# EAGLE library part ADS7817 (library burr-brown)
12-Bit Diff. Input Micro Power Sampling ADC

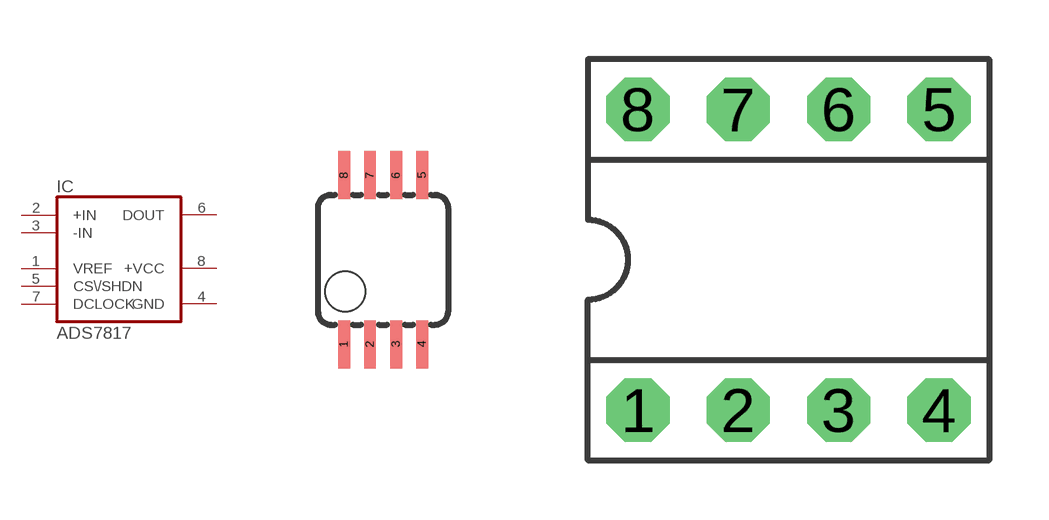
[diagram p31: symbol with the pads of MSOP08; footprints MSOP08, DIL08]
Designator prefix IC

## ADS7817E  [MSOP08]
1  VREF  in
2  +IN  in
3  -IN  in
4  GND  pwr
5  CS\/SHDN  in
6  DOUT  out
7  DCLOCK  in
8  +VCC  pwr

## ADS7817P  [DIL08]
Pads as for MSOP08

## ADS7817U  [SO08-GW]
Pads as for MSOP08

## Footprint MSOP08 (pad centres in mm)
Mini Small Outline Package
smd 0.3 x 1.2: 1 -0.976,-2.113; 2 -0.326,-2.113; 3 0.324,-2.113; 4 0.974,-2.113; 5 0.974,2.112; 6 0.324,2.112; 7 -0.326,2.112; 8 -0.976,2.112

## Footprint DIL08 (pad centres in mm)
Dual In Line
drill 0.813 pad 1.6 octagon: 1 -3.81,-3.81; 2 -1.27,-3.81; 3 1.27,-3.81; 4 3.81,-3.81; 5 3.81,3.81; 6 1.27,3.81; 7 -1.27,3.81; 8 -3.81,3.81

## Footprint SO08-GW (pad centres in mm)
Small Outline Package, gull wing
smd 0.762 x 2.21: 1 -3.81,-4.318; 2 -1.27,-4.318; 3 1.27,-4.318; 4 3.81,-4.318; 5 3.81,4.318; 6 1.27,4.318; 7 -1.27,4.318; 8 -3.81,4.318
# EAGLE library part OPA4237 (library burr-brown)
Single-Supply Operational Amplifiers MicroAmplifier(TM) Series

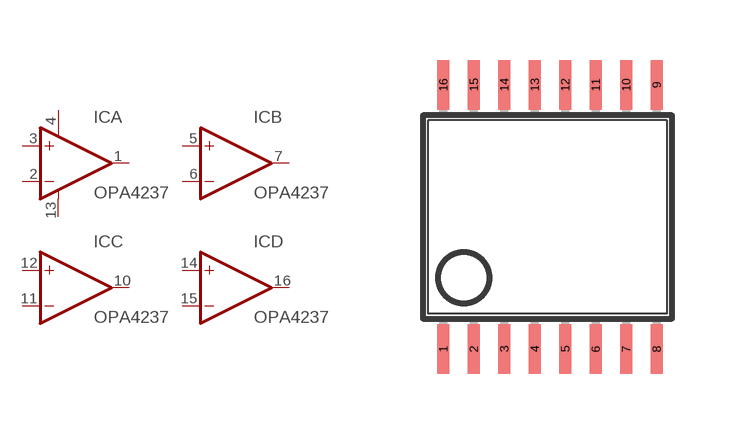
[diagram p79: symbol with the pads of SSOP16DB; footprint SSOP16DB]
Designator prefix IC; gates A=OP-AMP+- B=OP-AMP C=OP-AMP D=OP-AMP

## OPA4237U  [SSOP16DB]
1  A:OUT  out
2  A:-IN  in
3  A:+IN  in
4  A:V+  pwr
5  B:+IN  in
6  B:-IN  in
7  B:OUT  out
10  C:OUT  out
11  C:-IN  in
12  C:+IN  in
13  A:V-  pwr
14  D:+IN  in
15  D:-IN  in
16  D:OUT  out

## Footprint SSOP16DB (pad centres in mm)
Small Shrink Outline Package
smd 0.305 x 1.245: 1 -2.667,-3.302; 2 -1.905,-3.302; 3 -1.143,-3.302; 4 -0.381,-3.302; 5 0.381,-3.302; 6 1.143,-3.302; 7 1.905,-3.302; 8 2.667,-3.302; 9 2.667,3.302; 10 1.905,3.302; 11 1.143,3.302; 12 0.381,3.302; 13 -0.381,3.302; 14 -1.143,3.302; 15 -1.905,3.302; 16 -2.667,3.302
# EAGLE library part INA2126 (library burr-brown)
Instrumentation Amplifier Micropower, Single and Dual Versions

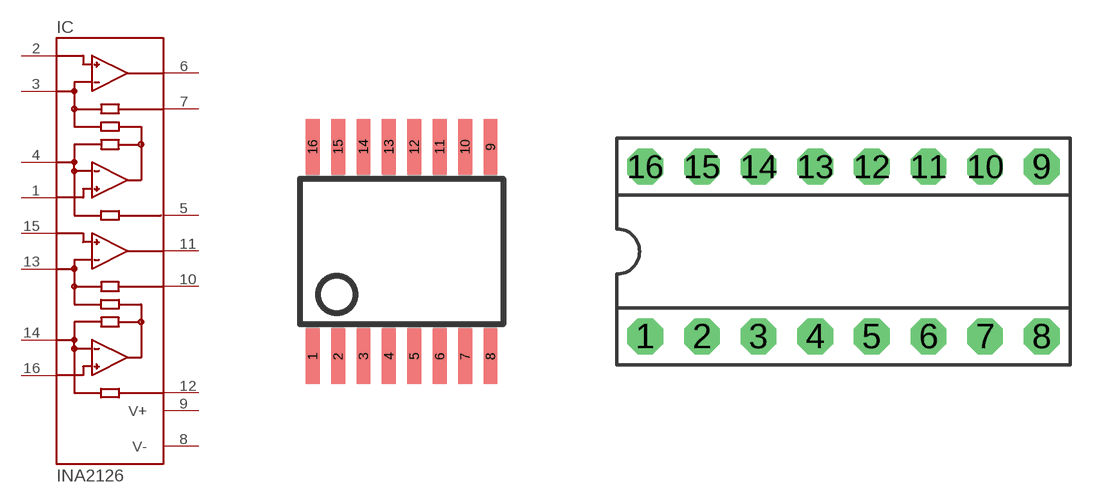
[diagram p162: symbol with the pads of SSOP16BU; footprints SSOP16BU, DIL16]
Designator prefix IC

## INA2126E  [SSOP16BU]
1  -INA  in
2  +INA  in
3  RGA  pas
4  RGA  pas
5  REFA  pwr
6  OUTA  out
7  SENSEA  pas
8  V-  pwr
9  V+  pwr
10  SENSEB  pas
11  OUTB  out
12  REFB  pwr
13  RGB  pas
14  RGB  pas
15  +INB  in
16  -INB  in

## INA2126P  [DIL16]
Pads as for SSOP16BU

## INA2126U  [SO16-1]
Pads as for SSOP16BU

## Footprint SSOP16BU (pad centres in mm)
Small Shrink Outline Package
smd 0.348 x 1.397: 1 -2.223,-2.619; 2 -1.588,-2.62; 3 -0.953,-2.62; 4 -0.318,-2.62; 5 0.318,-2.62; 6 0.953,-2.62; 7 1.588,-2.62; 8 2.223,-2.62; 9 2.223,2.62; 10 1.588,2.62; 11 0.953,2.62; 12 0.318,2.62; 13 -0.318,2.62; 14 -0.953,2.62; 15 -1.588,2.62; 16 -2.223,2.62

## Footprint DIL16 (pad centres in mm)
Dual In Line
drill 0.813 pad 1.6 octagon: 1 -8.89,-3.81; 2 -6.35,-3.81; 3 -3.81,-3.81; 4 -1.27,-3.81; 5 1.27,-3.81; 6 3.81,-3.81; 7 6.35,-3.81; 8 8.89,-3.81; 9 8.89,3.81; 10 6.35,3.81; 11 3.81,3.81; 12 1.27,3.81; 13 -1.27,3.81; 14 -3.81,3.81; 15 -6.35,3.81; 16 -8.89,3.81

## Footprint SO16-1 (pad centres in mm)
Small Outline Package
smd 0.762 x 1.524: 1 -4.445,-4.775; 2 -3.175,-4.775; 3 -1.905,-4.775; 4 -0.635,-4.775; 5 0.635,-4.775; 6 1.905,-4.775; 7 3.175,-4.775; 8 4.445,-4.775; 9 4.445,4.775; 10 3.175,4.775; 11 1.905,4.775; 12 0.635,4.775; 13 -0.635,4.775; 14 -1.905,4.775; 15 -3.175,4.775; 16 -4.445,4.775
